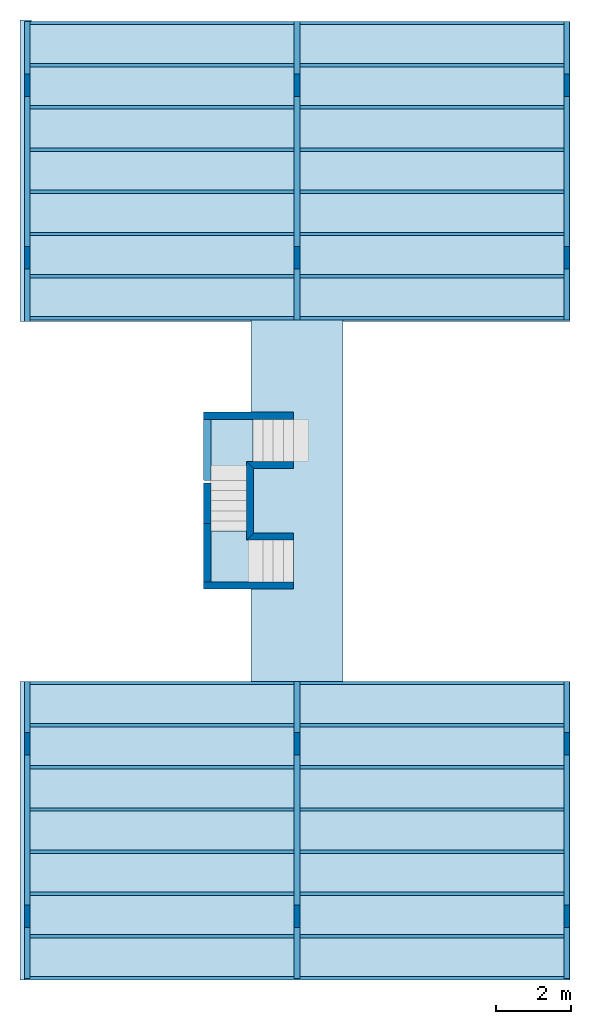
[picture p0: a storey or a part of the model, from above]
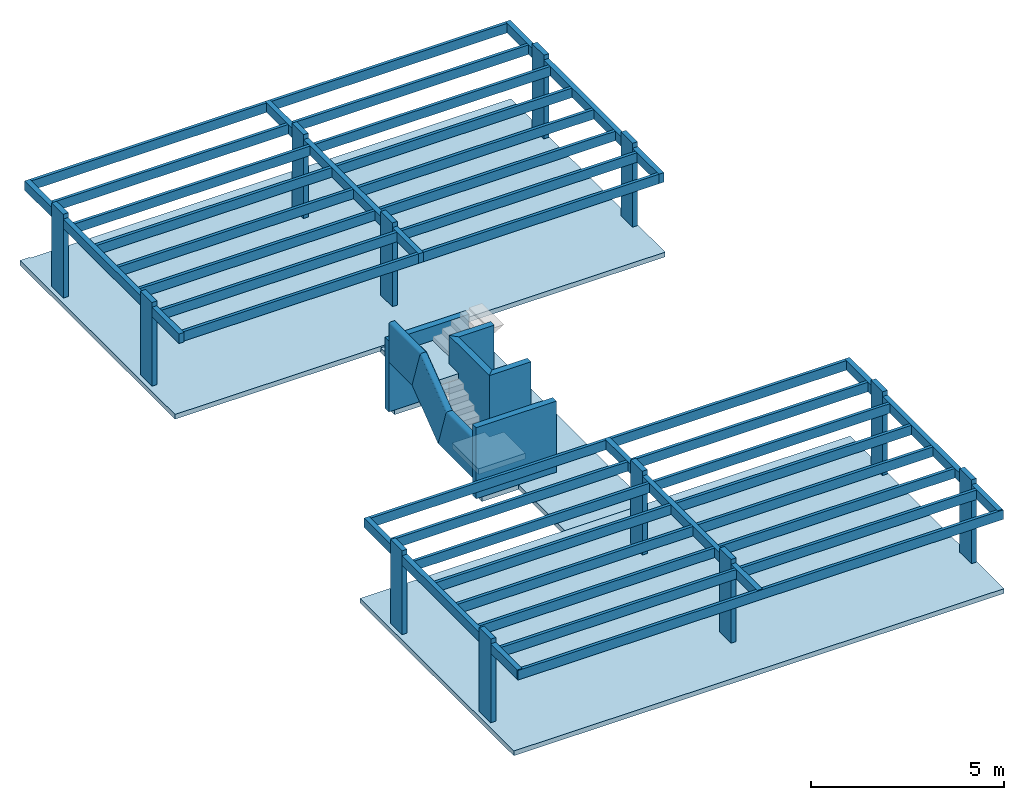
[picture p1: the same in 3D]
Properties of the parts of a building model (IFC4), part 6 of 7

# IfcWall: Concreto Armado Moldado in Loco - Estrutural 50 (48)
Name | In | ID Dinâmico por Classificação | Length (mm) = Comprimento Médio da Parede (mm) = Comprimento da parede no centro (mm) | Elevação à Origem do Projeto (mm) = Elevação ao 1º Nível de Referência (mm) = Elevação ao 2º Nível de Referência (mm) = Elevação ao Nível do Mar (mm) | Volume (Bruto) (m3) | Perímetro na Planta (mm) | Elevação do Topo ao Primeiro Nível de Referência (mm) = Elevação do Topo À Cota Zero (mm) = Elevação do Topo Ao Nível do Mar (mm) = Elevação do Topo Ao Segundo Nível de Referência (mm) | Elevação da Base Ao Primeiro Nível de Referência (mm) = Elevação da Base À Cota Zero (mm) = Elevação da Base Ao Nível do Mar (mm) = Elevação da Base Ao Segundo Nível de Referência (mm) | Comprimento da Linha de Referência (mm) = Comprimento da Face Externa da Parede (Condicional) (mm) = Comprimento da Parede na Face Externa (mm) | Comprimento da Face Interna da Parede (Condicional) (mm) = Comprimento da Parede na Face Interna (mm) | Área da Superfície da Face Interna da Parede (Bruta) (m2) = Área da Superfície da Face Externa da Parede (Bruta) (m2)
APTO4-PAREDE-002 | Primeiro Pavimento | Parede -002 | 470 | 0 | 0.032385 | 1084.34 | 1235 | 100 | 430 | 510 | 0.6477
APTO4-PAREDE-001 | Primeiro Pavimento | Parede -001 | 435 | 0 | 0.0276225 | 970 | 1235 | 100 | 435 | 435 | 0.55245
APTO4-PAREDE-018 | Primeiro Pavimento | Parede -018 | 470 | 0 | 0.032385 | 1084.34 | 1235 | 100 | 430 | 510 | 0.6477
APTO4-PAREDE-016 | Primeiro Pavimento | Parede -016 | 435 | 0 | 0.0276225 | 970 | 1235 | 100 | 435 | 435 | 0.55245
APTO2-PAREDE-016 | Primeiro Pavimento | Parede -016 | 435 | 0 | 0.0276225 | 970 | 1235 | 100 | 435 | 435 | 0.55245
APTO2-PAREDE-018 | Primeiro Pavimento | Parede -018 | 470 | 0 | 0.032385 | 1084.34 | 1235 | 100 | 430 | 510 | 0.6477
APTO2-PAREDE-002 | Primeiro Pavimento | Parede -002 | 470 | 0 | 0.032385 | 1084.34 | 1235 | 100 | 430 | 510 | 0.6477
APTO2-PAREDE-001 | Primeiro Pavimento | Parede -001 | 435 | 0 | 0.0276225 | 970 | 1235 | 100 | 435 | 435 | 0.55245
APTO3-PAREDE-016 | Primeiro Pavimento | Parede -016 | 435 | 0 | 0.0276225 | 970 | 1235 | 100 | 435 | 435 | 0.55245
APTO3-PAREDE-018 | Primeiro Pavimento | Parede -018 | 470 | 0 | 0.032385 | 1084.34 | 1235 | 100 | 430 | 510 | 0.6477
APTO3-PAREDE-002 | Primeiro Pavimento | Parede -002 | 470 | 0 | 0.032385 | 1084.34 | 1235 | 100 | 430 | 510 | 0.6477
APTO3-PAREDE-001 | Primeiro Pavimento | Parede -001 | 435 | 0 | 0.0276225 | 970 | 1235 | 100 | 435 | 435 | 0.55245
APTO1-PAREDE-001 | Primeiro Pavimento | Parede -001 | 435 | 0 | 0.0276225 | 970 | 1235 | 100 | 435 | 435 | 0.55245
APTO1-PAREDE-002 | Primeiro Pavimento | Parede -002 | 470 | 0 | 0.032385 | 1084.34 | 1235 | 100 | 430 | 510 | 0.6477
APTO1-PAREDE-018 | Primeiro Pavimento | Parede -018 | 470 | 0 | 0.032385 | 1084.34 | 1235 | 100 | 430 | 510 | 0.6477
APTO1-PAREDE-016 | Primeiro Pavimento | Parede -016 | 435 | 0 | 0.0276225 | 970 | 1235 | 100 | 435 | 435 | 0.55245
APTO5-PAREDE-016 | Segundo Pavimento | Parede -016 | 435 | 2650 | 0.0276225 | 970 | 3885 | 2750 | 435 | 435 | 0.55245
APTO5-PAREDE-018 | Segundo Pavimento | Parede -018 | 470 | 2650 | 0.032385 | 1084.34 | 3885 | 2750 | 430 | 510 | 0.6477
APTO5-PAREDE-002 | Segundo Pavimento | Parede -002 | 470 | 2650 | 0.032385 | 1084.34 | 3885 | 2750 | 430 | 510 | 0.6477
APTO5-PAREDE-001 | Segundo Pavimento | Parede -001 | 435 | 2650 | 0.0276225 | 970 | 3885 | 2750 | 435 | 435 | 0.55245
APTO6-PAREDE-016 | Segundo Pavimento | Parede -016 | 435 | 2650 | 0.0276225 | 970 | 3885 | 2750 | 435 | 435 | 0.55245
APTO6-PAREDE-018 | Segundo Pavimento | Parede -018 | 470 | 2650 | 0.032385 | 1084.34 | 3885 | 2750 | 430 | 510 | 0.6477
APTO6-PAREDE-002 | Segundo Pavimento | Parede -002 | 470 | 2650 | 0.032385 | 1084.34 | 3885 | 2750 | 430 | 510 | 0.6477
APTO6-PAREDE-001 | Segundo Pavimento | Parede -001 | 435 | 2650 | 0.0276225 | 970 | 3885 | 2750 | 435 | 435 | 0.55245
APTO7-PAREDE-016 | Segundo Pavimento | Parede -016 | 435 | 2650 | 0.0276225 | 970 | 3885 | 2750 | 435 | 435 | 0.55245
APTO7-PAREDE-018 | Segundo Pavimento | Parede -018 | 470 | 2650 | 0.032385 | 1084.34 | 3885 | 2750 | 430 | 510 | 0.6477
APTO7-PAREDE-002 | Segundo Pavimento | Parede -002 | 470 | 2650 | 0.032385 | 1084.34 | 3885 | 2750 | 430 | 510 | 0.6477
APTO7-PAREDE-001 | Segundo Pavimento | Parede -001 | 435 | 2650 | 0.0276225 | 970 | 3885 | 2750 | 435 | 435 | 0.55245
APTO8-PAREDE-016 | Segundo Pavimento | Parede -016 | 435 | 2650 | 0.0276225 | 970 | 3885 | 2750 | 435 | 435 | 0.55245
APTO8-PAREDE-018 | Segundo Pavimento | Parede -018 | 470 | 2650 | 0.032385 | 1084.34 | 3885 | 2750 | 430 | 510 | 0.6477
APTO8-PAREDE-002 | Segundo Pavimento | Parede -002 | 470 | 2650 | 0.032385 | 1084.34 | 3885 | 2750 | 430 | 510 | 0.6477
APTO8-PAREDE-001 | Segundo Pavimento | Parede -001 | 435 | 2650 | 0.0276225 | 970 | 3885 | 2750 | 435 | 435 | 0.55245
APTO9-PAREDE-016 | Terceiro Pavimento | Parede -016 | 435 | 5300 | 0.0276225 | 970 | 6535 | 5400 | 435 | 435 | 0.55245
APTO9-PAREDE-018 | Terceiro Pavimento | Parede -018 | 470 | 5300 | 0.032385 | 1084.34 | 6535 | 5400 | 430 | 510 | 0.6477
APTO9-PAREDE-002 | Terceiro Pavimento | Parede -002 | 470 | 5300 | 0.032385 | 1084.34 | 6535 | 5400 | 430 | 510 | 0.6477
APTO9-PAREDE-001 | Terceiro Pavimento | Parede -001 | 435 | 5300 | 0.0276225 | 970 | 6535 | 5400 | 435 | 435 | 0.55245
APTO10-PAREDE-016 | Terceiro Pavimento | Parede -016 | 435 | 5300 | 0.0276225 | 970 | 6535 | 5400 | 435 | 435 | 0.55245
APTO10-PAREDE-018 | Terceiro Pavimento | Parede -018 | 470 | 5300 | 0.032385 | 1084.34 | 6535 | 5400 | 430 | 510 | 0.6477
APTO10-PAREDE-002 | Terceiro Pavimento | Parede -002 | 470 | 5300 | 0.032385 | 1084.34 | 6535 | 5400 | 430 | 510 | 0.6477
APTO10-PAREDE-001 | Terceiro Pavimento | Parede -001 | 435 | 5300 | 0.0276225 | 970 | 6535 | 5400 | 435 | 435 | 0.55245
APTO11-PAREDE-016 | Terceiro Pavimento | Parede -016 | 435 | 5300 | 0.0276225 | 970 | 6535 | 5400 | 435 | 435 | 0.55245
APTO11-PAREDE-018 | Terceiro Pavimento | Parede -018 | 470 | 5300 | 0.032385 | 1084.34 | 6535 | 5400 | 430 | 510 | 0.6477
APTO11-PAREDE-002 | Terceiro Pavimento | Parede -002 | 470 | 5300 | 0.032385 | 1084.34 | 6535 | 5400 | 430 | 510 | 0.6477
APTO11-PAREDE-001 | Terceiro Pavimento | Parede -001 | 435 | 5300 | 0.0276225 | 970 | 6535 | 5400 | 435 | 435 | 0.55245
APTO12-PAREDE-016 | Terceiro Pavimento | Parede -016 | 435 | 5300 | 0.0276225 | 970 | 6535 | 5400 | 435 | 435 | 0.55245
APTO12-PAREDE-018 | Terceiro Pavimento | Parede -018 | 470 | 5300 | 0.032385 | 1084.34 | 6535 | 5400 | 430 | 510 | 0.6477
APTO12-PAREDE-002 | Terceiro Pavimento | Parede -002 | 470 | 5300 | 0.032385 | 1084.34 | 6535 | 5400 | 430 | 510 | 0.6477
APTO12-PAREDE-001 | Terceiro Pavimento | Parede -001 | 435 | 5300 | 0.0276225 | 970 | 6535 | 5400 | 435 | 435 | 0.55245

# IfcWall: Concreto Armado Moldado in Loco - Estrutural 80 (24)
Classification: Parede (Classificação ARCHICAD); 3E 14 02 00 Parede (NBR 15965-5 3E); Material: Concreto Armado Moldado in Loco - Estrutural 80 mm
Pset_WallCommon - AcousticRating: 0,00; IsExternal: yes; Status: EXISTING
CLASSIFICAÇÕES GERAIS - Transmissão Sonora: 0
SUPERFÍCIES (Mapas) - Superfície da Face (Geral): Concreto - 03
Component Properties - Concreto Armado Moldado in Loco - Estrutural, Tipo de Componente: Nenhum
Qto_WallBaseQuantities - Height: 1685 mm; Width: 80 mm; Concreto Armado Moldado in Loco - Estrutural, Width: 80 mm
ArchiCADQuantities - Altura: 1765 mm; Largura: 80 mm; Elevação ao Piso: -450 mm; Afastamento da Origem: -450 mm; Afastamento do Topo: 0 mm; Espessura: 80 mm; Espessura da Camada de Isolamento: 0 mm; Elevação do Topo Ao Piso de Origem: 1235 mm; Elevação da Base Ao Piso de Origem: -450 mm; Número de Portas: 0; Número de Furos (Número de Aberturas Vazias): 0; Número de Janelas: 0; Número de Pilares: 0; Volume dos Pilares: 0 m3; Altura Máxima da Camada da Parede na Face Interna: 0 mm; Altura Mínima da Camada da Parede na Face Interna: 0 mm; Altura máxima da parede: 1685 mm; Altura mínima da parede: 0 mm; Altura Máxima da Camada da Parede na Face Externa: 0 mm; Altura Mínima da Camada da Parede na Face Externa: 0 mm; Espessura da Camada de Ar: 0 mm; Área das Portas: 0 m2; Soma das Larguras das Portas: 0 mm; Espessura do Componente na Face Interna da Parede: 0 mm; Espessura do Componentena na Face Externa da Parede: 0 mm; Área das Janelas: 0 m2; Soma das Larguras das Janelas: 0 mm; Área Analítica da Superfície das Aberturas da Face Interna: 0 m2; Área Analítica da Superfície das Aberturas da Face Externa: 0 m2; Volume Analítico das Aberturas: 0 m3; Espessura da Parede na Terminação: 80 mm; Área de Superfície do Vão na Parede: 0 m2
ALVENARIAS (Expressão) - Espessura da Argamassa: 10 mm
Component Quantities - Concreto Armado Moldado in Loco - Estrutural, Espessura do Componente: 80 mm; Concreto Armado Moldado in Loco - Estrutural, Altura do Componente Retangular: 1765 mm; Concreto Armado Moldado in Loco - Estrutural, Largura do Componente Retangular: 80 mm; Concreto Armado Moldado in Loco - Estrutural, Área de Seção Transversal do Componente: 0.1412 m2
Name | In | ID Dinâmico por Classificação | Concreto Armado Moldado in Loco - Estrutural, Carbono Incorporado | Concreto Armado Moldado in Loco - Estrutural, Energia Incorporada (MJ) | Length (mm) = Comprimento Médio da Parede (mm) = Comprimento da parede no centro (mm) | GrossFootprintArea (m2) = NetFootprintArea (m2) = Área (m2) = Área da Superfície do Topo (Líquida) (m2) | GrossSideArea (m2) = NetSideArea (m2) = Área da Superfície (m2) = Área da Superfície da Base (Líquida) (m2) = Área da Superfície da Face Interna da Parede (Líquida) (m2) = Área da Superfície da Face Externa da Parede (Líquida) (m2) = Área da Superfície da Face Interna da Parede (Condicional) (m2) = Área da Superfície da Face Externa da Parede (Condicional) (m2) = Concreto Armado Moldado in Loco - Estrutural, Área de Componente Projetada (Líquida) (m2) = Concreto Armado Moldado in Loco - Estrutural, Área de Componente Projetada (Bruta) (m2) = Concreto Armado Moldado in Loco - Estrutural, Área de Componente Projetada (Condicional) (m2) | GrossVolume (m3) = NetVolume (m3) = Volume (Líquido) (m3) = Volume (Condicional) (m3) = Concreto Armado Moldado in Loco - Estrutural, Volume Componente (Líquido) (m3) = Concreto Armado Moldado in Loco - Estrutural, Volume do componente (Bruto) (m3) = Concreto Armado Moldado in Loco - Estrutural, Volume Componente (Condicional) (m3) | Elevação à Origem do Projeto (mm) = Elevação ao 1º Nível de Referência (mm) = Elevação ao 2º Nível de Referência (mm) = Elevação ao Nível do Mar (mm) = Elevação da Base Ao Primeiro Nível de Referência (mm) = Elevação da Base À Cota Zero (mm) = Elevação da Base Ao Nível do Mar (mm) = Elevação da Base Ao Segundo Nível de Referência (mm) | Comprimento 3D (mm) = Comprimento da Linha de Referência (mm) = Comprimento da Face Externa da Parede (Condicional) (mm) = Comprimento da Parede na Face Externa (mm) | Volume (Bruto) (m3) | Perímetro na Planta (mm) | Elevação do Topo ao Primeiro Nível de Referência (mm) = Elevação do Topo À Cota Zero (mm) = Elevação do Topo Ao Nível do Mar (mm) = Elevação do Topo Ao Segundo Nível de Referência (mm) | Área da Superfície da Borda (Líquida) (m2) = Área da Superfície da Face (Geral) (m2) | Comprimento da Face Interna da Parede (Condicional) (mm) = Comprimento da Parede na Face Interna (mm) | Área da Superfície da Face Interna da Parede (Bruta) (m2) = Área da Superfície da Face Externa da Parede (Bruta) (m2) | Concreto Armado Moldado in Loco - Estrutural, Massa (kg)
APTO4-PAREDE-015 | Primeiro Pavimento | Parede -015 | 514.045 (kgCO₂) | 4949.28 | 6955 | 0.5584 | 11.0633 | 0.885064 | -450 | 6980 | 0.985576 | 14084.3 | 1235 | 0.6852 | 6930 | 12.3197 | 2124.15
APTO4-PAREDE-017 | Primeiro Pavimento | Parede -017 | 412.414 (kgCO₂) | 3970.77 | 5575 | 0.448 | 8.876 | 0.71008 | -450 | 5600 | 0.79072 | 11324.3 | 1235 | 0.5748 | 5550 | 9.884 | 1704.19
APTO2-PAREDE-017 | Primeiro Pavimento | Parede -017 | 412.414 (kgCO₂) | 3970.77 | 5575 | 0.448 | 8.876 | 0.71008 | -450 | 5600 | 0.79072 | 11324.3 | 1235 | 0.5748 | 5550 | 9.884 | 1704.19
APTO2-PAREDE-015 | Primeiro Pavimento | Parede -015 | 514.045 (kgCO₂) | 4949.28 | 6955 | 0.5584 | 11.0633 | 0.885064 | -450 | 6980 | 0.985576 | 14084.3 | 1235 | 0.6852 | 6930 | 12.3197 | 2124.15
APTO3-PAREDE-017 | Primeiro Pavimento | Parede -017 | 412.414 (kgCO₂) | 3970.77 | 5575 | 0.448 | 8.876 | 0.71008 | -450 | 5600 | 0.79072 | 11324.3 | 1235 | 0.5748 | 5550 | 9.884 | 1704.19
APTO3-PAREDE-015 | Primeiro Pavimento | Parede -015 | 514.045 (kgCO₂) | 4949.28 | 6955 | 0.5584 | 11.0633 | 0.885064 | -450 | 6980 | 0.985576 | 14084.3 | 1235 | 0.6852 | 6930 | 12.3197 | 2124.15
APTO1-PAREDE-015 | Primeiro Pavimento | Parede -015 | 514.045 (kgCO₂) | 4949.28 | 6955 | 0.5584 | 11.0633 | 0.885064 | -450 | 6980 | 0.985576 | 14084.3 | 1235 | 0.6852 | 6930 | 12.3197 | 2124.15
APTO1-PAREDE-017 | Primeiro Pavimento | Parede -017 | 412.414 (kgCO₂) | 3970.77 | 5575 | 0.448 | 8.876 | 0.71008 | -450 | 5600 | 0.79072 | 11324.3 | 1235 | 0.5748 | 5550 | 9.884 | 1704.19
APTO5-PAREDE-017 | Segundo Pavimento | Parede -017 | 412.414 (kgCO₂) | 3970.77 | 5575 | 0.448 | 8.876 | 0.71008 | 2200 | 5600 | 0.79072 | 11324.3 | 3885 | 0.5748 | 5550 | 9.884 | 1704.19
APTO5-PAREDE-015 | Segundo Pavimento | Parede -015 | 514.045 (kgCO₂) | 4949.28 | 6955 | 0.5584 | 11.0633 | 0.885064 | 2200 | 6980 | 0.985576 | 14084.3 | 3885 | 0.6852 | 6930 | 12.3197 | 2124.15
APTO6-PAREDE-017 | Segundo Pavimento | Parede -017 | 412.414 (kgCO₂) | 3970.77 | 5575 | 0.448 | 8.876 | 0.71008 | 2200 | 5600 | 0.79072 | 11324.3 | 3885 | 0.5748 | 5550 | 9.884 | 1704.19
APTO6-PAREDE-015 | Segundo Pavimento | Parede -015 | 514.045 (kgCO₂) | 4949.28 | 6955 | 0.5584 | 11.0633 | 0.885064 | 2200 | 6980 | 0.985576 | 14084.3 | 3885 | 0.6852 | 6930 | 12.3197 | 2124.15
APTO7-PAREDE-017 | Segundo Pavimento | Parede -017 | 412.414 (kgCO₂) | 3970.77 | 5575 | 0.448 | 8.876 | 0.71008 | 2200 | 5600 | 0.79072 | 11324.3 | 3885 | 0.5748 | 5550 | 9.884 | 1704.19
APTO7-PAREDE-015 | Segundo Pavimento | Parede -015 | 514.045 (kgCO₂) | 4949.28 | 6955 | 0.5584 | 11.0633 | 0.885064 | 2200 | 6980 | 0.985576 | 14084.3 | 3885 | 0.6852 | 6930 | 12.3197 | 2124.15
APTO8-PAREDE-017 | Segundo Pavimento | Parede -017 | 412.414 (kgCO₂) | 3970.77 | 5575 | 0.448 | 8.876 | 0.71008 | 2200 | 5600 | 0.79072 | 11324.3 | 3885 | 0.5748 | 5550 | 9.884 | 1704.19
APTO8-PAREDE-015 | Segundo Pavimento | Parede -015 | 514.045 (kgCO₂) | 4949.28 | 6955 | 0.5584 | 11.0633 | 0.885064 | 2200 | 6980 | 0.985576 | 14084.3 | 3885 | 0.6852 | 6930 | 12.3197 | 2124.15
APTO9-PAREDE-017 | Terceiro Pavimento | Parede -017 | 412.414 (kgCO₂) | 3970.77 | 5575 | 0.448 | 8.876 | 0.71008 | 4850 | 5600 | 0.79072 | 11324.3 | 6535 | 0.5748 | 5550 | 9.884 | 1704.19
APTO9-PAREDE-015 | Terceiro Pavimento | Parede -015 | 514.045 (kgCO₂) | 4949.28 | 6955 | 0.5584 | 11.0633 | 0.885064 | 4850 | 6980 | 0.985576 | 14084.3 | 6535 | 0.6852 | 6930 | 12.3197 | 2124.15
APTO10-PAREDE-017 | Terceiro Pavimento | Parede -017 | 412.414 (kgCO₂) | 3970.77 | 5575 | 0.448 | 8.876 | 0.71008 | 4850 | 5600 | 0.79072 | 11324.3 | 6535 | 0.5748 | 5550 | 9.884 | 1704.19
APTO10-PAREDE-015 | Terceiro Pavimento | Parede -015 | 514.045 (kgCO₂) | 4949.28 | 6955 | 0.5584 | 11.0633 | 0.885064 | 4850 | 6980 | 0.985576 | 14084.3 | 6535 | 0.6852 | 6930 | 12.3197 | 2124.15
APTO11-PAREDE-017 | Terceiro Pavimento | Parede -017 | 412.414 (kgCO₂) | 3970.77 | 5575 | 0.448 | 8.876 | 0.71008 | 4850 | 5600 | 0.79072 | 11324.3 | 6535 | 0.5748 | 5550 | 9.884 | 1704.19
APTO11-PAREDE-015 | Terceiro Pavimento | Parede -015 | 514.045 (kgCO₂) | 4949.28 | 6955 | 0.5584 | 11.0633 | 0.885064 | 4850 | 6980 | 0.985576 | 14084.3 | 6535 | 0.6852 | 6930 | 12.3197 | 2124.15
APTO12-PAREDE-017 | Terceiro Pavimento | Parede -017 | 412.414 (kgCO₂) | 3970.77 | 5575 | 0.448 | 8.876 | 0.71008 | 4850 | 5600 | 0.79072 | 11324.3 | 6535 | 0.5748 | 5550 | 9.884 | 1704.19
APTO12-PAREDE-015 | Terceiro Pavimento | Parede -015 | 514.045 (kgCO₂) | 4949.28 | 6955 | 0.5584 | 11.0633 | 0.885064 | 4850 | 6980 | 0.985576 | 14084.3 | 6535 | 0.6852 | 6930 | 12.3197 | 2124.15

# IfcWall: GENÉRICO - VEDAÇÃO EXTERNA 140 (12)
Classification: Parede (Classificação ARCHICAD); 3E 14 02 00 Parede (NBR 15965-5 3E); Material: GENÉRICO - VEDAÇÃO EXTERNA 140 mm
Pset_WallCommon - AcousticRating: 0,00; IsExternal: yes; Status: EXISTING
CLASSIFICAÇÕES GERAIS - Transmissão Sonora: 0
EXPRESSÕES DE TEXTO (Expressão) - ID Dinâmico por Classificação: Parede -004
SUPERFÍCIES (Mapas) - Superfície da Face (Geral): Pintura - Sienna Areia
Component Properties - GENÉRICO - VEDAÇÃO EXTERNA, Tipo de Componente: Nenhum
Qto_WallBaseQuantities - Length: 1580 mm; Height: 2200 mm; Width: 140 mm; GENÉRICO - VEDAÇÃO EXTERNA, Width: 140 mm
ArchiCADQuantities - Altura: 2200 mm; Largura: 140 mm; Elevação ao Piso: 0 mm; Afastamento da Origem: 0 mm; Afastamento do Topo: -450 mm; Espessura: 140 mm; Espessura da Camada de Isolamento: 0 mm; Perímetro na Planta: 3440 mm; Elevação do Topo Ao Piso de Origem: 2200 mm; Elevação da Base Ao Piso de Origem: 0 mm; Número de Portas: 1; Número de Furos (Número de Aberturas Vazias): 0; Número de Janelas: 0; Número de Pilares: 0; Volume dos Pilares: 0 m3; Altura Máxima da Camada da Parede na Face Interna: 0 mm; Altura Mínima da Camada da Parede na Face Interna: 0 mm; Altura máxima da parede: 2200 mm; Altura Máxima da Camada da Parede na Face Externa: 0 mm; Altura Mínima da Camada da Parede na Face Externa: 0 mm; Espessura da Camada de Ar: 0 mm; Área das Portas: 1.89 m2; Soma das Larguras das Portas: 900 mm; Espessura do Componente na Face Interna da Parede: 0 mm; Espessura do Componentena na Face Externa da Parede: 0 mm; Área das Janelas: 0 m2; Soma das Larguras das Janelas: 0 mm; Área Analítica da Superfície das Aberturas da Face Interna: 1.89 m2; Área Analítica da Superfície das Aberturas da Face Externa: 1.89 m2; Comprimento Médio da Parede: 1580 mm; Volume Analítico das Aberturas: 0.2646 m3; Comprimento da Linha de Referência: 1580 mm; Comprimento da Face Interna da Parede (Condicional): 680 mm; Comprimento da Face Externa da Parede (Condicional): 680 mm; Espessura da Parede na Terminação: 140 mm; Comprimento da parede no centro: 1580 mm; Comprimento da Parede na Face Interna: 1580 mm; Comprimento da Parede na Face Externa: 1580 mm; Área de Superfície do Vão na Parede: 0 m2
ALVENARIAS (Expressão) - Espessura da Argamassa: 10 mm
Component Quantities - GENÉRICO - VEDAÇÃO EXTERNA, Espessura do Componente: 140 mm; GENÉRICO - VEDAÇÃO EXTERNA, Altura do Componente Retangular: 2200 mm; GENÉRICO - VEDAÇÃO EXTERNA, Largura do Componente Retangular: 140 mm; GENÉRICO - VEDAÇÃO EXTERNA, Área de Seção Transversal do Componente: 0.308 m2
Name | In | GENÉRICO - VEDAÇÃO EXTERNA, Carbono Incorporado | GENÉRICO - VEDAÇÃO EXTERNA, Energia Incorporada (MJ) | GrossFootprintArea (m2) = NetFootprintArea (m2) = Área (m2) = Área da Superfície do Topo (Líquida) (m2) | GrossSideArea (m2) = Área da Superfície da Face Interna da Parede (Condicional) (m2) = Área da Superfície da Face Externa da Parede (Condicional) (m2) = GENÉRICO - VEDAÇÃO EXTERNA, Área de Componente Projetada (Bruta) (m2) = GENÉRICO - VEDAÇÃO EXTERNA, Área de Componente Projetada (Condicional) (m2) | NetSideArea (m2) = Área da Superfície (m2) = Área da Superfície da Base (Líquida) (m2) = Área da Superfície da Face Interna da Parede (Líquida) (m2) = Área da Superfície da Face Externa da Parede (Líquida) (m2) = GENÉRICO - VEDAÇÃO EXTERNA, Área de Componente Projetada (Líquida) (m2) | GrossVolume (m3) = Volume (Condicional) (m3) = GENÉRICO - VEDAÇÃO EXTERNA, Volume do componente (Bruto) (m3) = GENÉRICO - VEDAÇÃO EXTERNA, Volume Componente (Condicional) (m3) | NetVolume (m3) = Volume (Líquido) (m3) = GENÉRICO - VEDAÇÃO EXTERNA, Volume Componente (Líquido) (m3) | Elevação à Origem do Projeto (mm) = Elevação ao 1º Nível de Referência (mm) = Elevação ao 2º Nível de Referência (mm) = Elevação ao Nível do Mar (mm) = Elevação da Base Ao Primeiro Nível de Referência (mm) = Elevação da Base À Cota Zero (mm) = Elevação da Base Ao Nível do Mar (mm) = Elevação da Base Ao Segundo Nível de Referência (mm) | Comprimento 3D (mm) | Volume (Bruto) (m3) | Elevação do Topo ao Primeiro Nível de Referência (mm) = Elevação do Topo À Cota Zero (mm) = Elevação do Topo Ao Nível do Mar (mm) = Elevação do Topo Ao Segundo Nível de Referência (mm) | Área da Superfície da Borda (Líquida) (m2) = Área da Superfície da Face (Geral) (m2) | Altura mínima da parede (mm) | Área da Superfície da Face Interna da Parede (Bruta) (m2) = Área da Superfície da Face Externa da Parede (Bruta) (m2) | GENÉRICO - VEDAÇÃO EXTERNA, Massa (kg)
APTO4-PAREDE-004 | Primeiro Pavimento | 76.737 (kgCO₂) | 959.213 | 0.0952 | 3.476 | 1.586 | 0.48664 | 0.22204 | 0 | 1580 | 0.48664 | 2200 | 0.9324 | 2200 | 3.476 | 213.158
APTO2-PAREDE-004 | Primeiro Pavimento | 76.737 (kgCO₂) | 959.213 | 0.0952 | 3.476 | 1.586 | 0.48664 | 0.22204 | 0 | 1580 | 0.48664 | 2200 | 0.9324 | 2200 | 3.476 | 213.158
APTO3-PAREDE-004 | Primeiro Pavimento | 56.5125 (kgCO₂) | 706.406 | 0.0686 | 3.058 | 1.168 | 0.42812 | 0.16352 | 0 | 1390 | 0.51744 | 2200 | 0.5712 | 2100 | 3.696 | 156.979
APTO1-PAREDE-004 | Primeiro Pavimento | 56.5125 (kgCO₂) | 706.406 | 0.0686 | 3.058 | 1.168 | 0.42812 | 0.16352 | 0 | 1390 | 0.51744 | 2200 | 0.5712 | 2100 | 3.696 | 156.979
APTO5-PAREDE-004 | Segundo Pavimento | 56.5125 (kgCO₂) | 706.406 | 0.0686 | 3.058 | 1.168 | 0.42812 | 0.16352 | 2650 | 1390 | 0.51744 | 4850 | 0.5712 | 2100 | 3.696 | 156.979
APTO6-PAREDE-004 | Segundo Pavimento | 76.737 (kgCO₂) | 959.213 | 0.0952 | 3.476 | 1.586 | 0.48664 | 0.22204 | 2650 | 1580 | 0.48664 | 4850 | 0.9324 | 2200 | 3.476 | 213.158
APTO7-PAREDE-004 | Segundo Pavimento | 56.5125 (kgCO₂) | 706.406 | 0.0686 | 3.058 | 1.168 | 0.42812 | 0.16352 | 2650 | 1390 | 0.51744 | 4850 | 0.5712 | 2100 | 3.696 | 156.979
APTO8-PAREDE-004 | Segundo Pavimento | 76.737 (kgCO₂) | 959.213 | 0.0952 | 3.476 | 1.586 | 0.48664 | 0.22204 | 2650 | 1580 | 0.48664 | 4850 | 0.9324 | 2200 | 3.476 | 213.158
APTO9-PAREDE-004 | Terceiro Pavimento | 56.5125 (kgCO₂) | 706.406 | 0.0686 | 3.058 | 1.168 | 0.42812 | 0.16352 | 5300 | 1390 | 0.51744 | 7500 | 0.5712 | 2100 | 3.696 | 156.979
APTO10-PAREDE-004 | Terceiro Pavimento | 76.737 (kgCO₂) | 959.213 | 0.0952 | 3.476 | 1.586 | 0.48664 | 0.22204 | 5300 | 1580 | 0.48664 | 7500 | 0.9324 | 2200 | 3.476 | 213.158
APTO11-PAREDE-004 | Terceiro Pavimento | 56.5125 (kgCO₂) | 706.406 | 0.0686 | 3.058 | 1.168 | 0.42812 | 0.16352 | 5300 | 1390 | 0.51744 | 7500 | 0.5712 | 2100 | 3.696 | 156.979
APTO12-PAREDE-004 | Terceiro Pavimento | 76.737 (kgCO₂) | 959.213 | 0.0952 | 3.476 | 1.586 | 0.48664 | 0.22204 | 5300 | 1580 | 0.48664 | 7500 | 0.9324 | 2200 | 3.476 | 213.158

# IfcWall: GENÉRICO - VEDAÇÃO EXTERNA 190 (26)
Classification: Parede (Classificação ARCHICAD); 3E 14 02 00 Parede (NBR 15965-5 3E); Material: GENÉRICO - VEDAÇÃO EXTERNA 190 mm
Pset_WallCommon - AcousticRating: 0,00; Status: EXISTING
CLASSIFICAÇÕES GERAIS - Transmissão Sonora: 0
SUPERFÍCIES (Mapas) - Superfície da Face (Geral): Pintura - Sienna Areia
Component Properties - GENÉRICO - VEDAÇÃO EXTERNA, Tipo de Componente: Nenhum
Qto_WallBaseQuantities - Width: 190 mm; GENÉRICO - VEDAÇÃO EXTERNA, Width: 190 mm
ArchiCADQuantities - Largura: 190 mm; Espessura: 190 mm; Espessura da Camada de Isolamento: 0 mm; Número de Portas: 0; Número de Furos (Número de Aberturas Vazias): 0; Número de Janelas: 0; Volume dos Pilares: 0 m3; Altura Máxima da Camada da Parede na Face Interna: 0 mm; Altura Mínima da Camada da Parede na Face Interna: 0 mm; Altura Máxima da Camada da Parede na Face Externa: 0 mm; Altura Mínima da Camada da Parede na Face Externa: 0 mm; Espessura da Camada de Ar: 0 mm; Área das Portas: 0 m2; Soma das Larguras das Portas: 0 mm; Espessura do Componente na Face Interna da Parede: 0 mm; Espessura do Componentena na Face Externa da Parede: 0 mm; Área das Janelas: 0 m2; Soma das Larguras das Janelas: 0 mm; Espessura da Parede na Terminação: 190 mm; Área de Superfície do Vão na Parede: 0 m2
ALVENARIAS (Expressão) - Espessura da Argamassa: 10 mm
Component Quantities - GENÉRICO - VEDAÇÃO EXTERNA, Espessura do Componente: 190 mm; GENÉRICO - VEDAÇÃO EXTERNA, Largura do Componente Retangular: 190 mm
Name | In | IsExternal | ID Dinâmico por Classificação | GENÉRICO - VEDAÇÃO EXTERNA, Carbono Incorporado | GENÉRICO - VEDAÇÃO EXTERNA, Energia Incorporada (MJ) | Length (mm) = Comprimento Médio da Parede (mm) = Comprimento da Linha de Referência (mm) = Comprimento da Face Interna da Parede (Condicional) (mm) = Comprimento da Face Externa da Parede (Condicional) (mm) = Comprimento da parede no centro (mm) = Comprimento da Parede na Face Interna (mm) = Comprimento da Parede na Face Externa (mm) | Height (mm) = Altura máxima da parede (mm) | GrossFootprintArea (m2) = NetFootprintArea (m2) = Área (m2) = Área da Superfície do Topo (Líquida) (m2) | GrossSideArea (m2) = NetSideArea (m2) | GrossVolume (m3) = NetVolume (m3) = Volume (Líquido) (m3) = Volume (Condicional) (m3) = GENÉRICO - VEDAÇÃO EXTERNA, Volume Componente (Líquido) (m3) = GENÉRICO - VEDAÇÃO EXTERNA, Volume do componente (Bruto) (m3) = GENÉRICO - VEDAÇÃO EXTERNA, Volume Componente (Condicional) (m3) | Altura (mm) = GENÉRICO - VEDAÇÃO EXTERNA, Altura do Componente Retangular (mm) | Elevação à Origem do Projeto (mm) = Elevação ao 1º Nível de Referência (mm) = Elevação ao 2º Nível de Referência (mm) = Elevação ao Nível do Mar (mm) = Elevação da Base Ao Primeiro Nível de Referência (mm) = Elevação da Base À Cota Zero (mm) = Elevação da Base Ao Nível do Mar (mm) = Elevação da Base Ao Segundo Nível de Referência (mm) | Elevação ao Piso (mm) = Afastamento da Origem (mm) = Elevação da Base Ao Piso de Origem (mm) | Afastamento do Topo (mm) | Área da Superfície (m2) = Área da Superfície da Base (Líquida) (m2) = Área da Superfície da Face Externa da Parede (Líquida) (m2) = Área da Superfície da Face Externa da Parede (Condicional) (m2) | Comprimento 3D (mm) | Volume (Bruto) (m3) | Perímetro na Planta (mm) | Elevação do Topo ao Primeiro Nível de Referência (mm) = Elevação do Topo À Cota Zero (mm) = Elevação do Topo Ao Nível do Mar (mm) = Elevação do Topo Ao Segundo Nível de Referência (mm) | Elevação do Topo Ao Piso de Origem (mm) | Área da Superfície da Borda (Líquida) (m2) = Área da Superfície da Face (Geral) (m2) | Número de Pilares | Altura mínima da parede (mm) | Área Analítica da Superfície das Aberturas da Face Interna (m2) | Área Analítica da Superfície das Aberturas da Face Externa (m2) | Área da Superfície da Face Interna da Parede (Líquida) (m2) = Área da Superfície da Face Interna da Parede (Condicional) (m2) | Volume Analítico das Aberturas (m3) | Área da Superfície da Face Interna da Parede (Bruta) (m2) = Área da Superfície da Face Externa da Parede (Bruta) (m2) | GENÉRICO - VEDAÇÃO EXTERNA, Massa (kg) | GENÉRICO - VEDAÇÃO EXTERNA, Área de Componente Projetada (Líquida) (m2) = GENÉRICO - VEDAÇÃO EXTERNA, Área de Componente Projetada (Bruta) (m2) = GENÉRICO - VEDAÇÃO EXTERNA, Área de Componente Projetada (Condicional) (m2) | GENÉRICO - VEDAÇÃO EXTERNA, Área de Seção Transversal do Componente (m2)
PAREDE-039 | Pavimento Terreo | yes | Parede -039 | 354.586 (kgCO₂) | 4432.32 | 2400 | 2250 | 0.456 | 5.4 | 1.026 | 2250 | -2700 | -50 | -450 | 5.4 | 2400 | 1.026 | 5180 | -450 | 2200 | 1.767 | 0 | 2250 | 0 | 0 | 5.4 | 0 | 5.4 | 984.96 | 5.4 | 0.4275
PAREDE-038 | Pavimento Terreo | yes | Parede -038 | 354.586 (kgCO₂) | 4432.32 | 2400 | 2250 | 0.456 | 5.4 | 1.026 | 2250 | -2700 | -50 | -450 | 5.4 | 2400 | 1.026 | 5180 | -450 | 2200 | 1.767 | 0 | 2250 | 0 | 0 | 5.4 | 0 | 5.4 | 984.96 | 5.4 | 0.4275
APTO4-PAREDE-013 | Primeiro Pavimento | yes | Parede -013 | 1051.33 (kgCO₂) | 13141.6 | 8000 | 2500 | 1.34 | 19.892 | 3.04204 | 2650 | 0 | 0 | 0 | 19.784 | 8000 | 4.028 | 16380 | 2500 | 2500 | 2.2615 | 2 | 0 | 0 | 0 | 20 | 0 | 21.2 | 2920.36 | 20 | 0.5035
CIRC1-PAREDE-021 | Primeiro Pavimento | yes | Parede -021 | 370.345 (kgCO₂) | 4629.31 | 2400 | 2350 | 0.456 | 5.64 | 1.0716 | 2350 | -150 | -150 | -450 | 5.64 | 2400 | 1.0716 | 5180 | 2200 | 2200 | 1.805 | 0 | 2350 | 0 | 0 | 5.64 | 0 | 5.64 | 1028.74 | 5.64 | 0.4465
CIRC1-PAREDE-020 | Primeiro Pavimento | yes | Parede -020 | 370.345 (kgCO₂) | 4629.31 | 2400 | 2350 | 0.456 | 5.64 | 1.0716 | 2350 | -150 | -150 | -450 | 5.64 | 2400 | 1.0716 | 5180 | 2200 | 2200 | 1.805 | 0 | 2350 | 0 | 0 | 5.64 | 0 | 5.64 | 1028.74 | 5.64 | 0.4465
APTO2-PAREDE-013 | Primeiro Pavimento | yes | Parede -013 | 1051.33 (kgCO₂) | 13141.6 | 8000 | 2500 | 1.34 | 19.892 | 3.04204 | 2650 | 0 | 0 | 0 | 19.784 | 8000 | 4.028 | 16380 | 2500 | 2500 | 2.2615 | 2 | 0 | 0 | -3.55271e-15 | 20 | 0 | 21.2 | 2920.36 | 20 | 0.5035
APTO3-PAREDE-013 | Primeiro Pavimento | yes | Parede -013 | 1051.33 (kgCO₂) | 13141.6 | 8000 | 2500 | 1.34 | 19.892 | 3.04204 | 2650 | 0 | 0 | 0 | 19.784 | 8000 | 4.028 | 16380 | 2500 | 2500 | 2.2615 | 2 | 0 | 0 | 0 | 20 | 0 | 21.2 | 2920.36 | 20 | 0.5035
APTO1-PAREDE-013 | Primeiro Pavimento | yes | Parede -013 | 1051.33 (kgCO₂) | 13141.6 | 8000 | 2500 | 1.34 | 19.892 | 3.04204 | 2650 | 0 | 0 | 0 | 19.784 | 8000 | 4.028 | 16380 | 2500 | 2500 | 2.2615 | 2 | 0 | 0 | 0 | 20 | 0 | 21.2 | 2920.36 | 20 | 0.5035
CIRC1-PAREDE-029 | Primeiro Pavimento | no | Parede -029 | 1023.39 (kgCO₂) | 12792.3 | 7825 | 2500 | 1.30675 | 19.3735 | 2.96119 | 2500 | 0 | 0 | -150 | 19.3735 | 7825 | 3.7754 | 16030 | 2500 | 2500 | 2.01255 | 2 | 0 | 0 | 0 | 19.3735 | -4.44089e-16 | 19.8705 | 2842.74 | 19.3735 | 0.475
CIRC1-PAREDE-026 | Primeiro Pavimento | no | Parede -026 | 1020.4 (kgCO₂) | 12755 | 7825 | 2470 | 1.30675 | 19.1577 | 2.95256 | 2470 | 0 | 0 | -180 | 19.1577 | 7825 | 3.73079 | 16030 | 2470 | 2470 | 2.01255 | 2 | 0 | 0 | 0 | 19.1577 | -4.44089e-16 | 19.6358 | 2834.45 | 19.1576 | 0.4693
CIRC2-PAREDE-020 | Segundo Pavimento | yes | Parede -020 | 370.345 (kgCO₂) | 4629.31 | 2400 | 2350 | 0.456 | 5.64 | 1.0716 | 2350 | 2500 | -150 | -450 | 5.64 | 2400 | 1.0716 | 5180 | 4850 | 2200 | 1.805 | 0 | 2350 | 0 | 0 | 5.64 | 0 | 5.64 | 1028.74 | 5.64 | 0.4465
CIRC2-PAREDE-026 | Segundo Pavimento | no | Parede -026 | 1020.4 (kgCO₂) | 12755 | 7825 | 2470 | 1.30675 | 19.1577 | 2.95256 | 2470 | 2650 | 0 | -180 | 19.1577 | 7825 | 3.73079 | 16030 | 5120 | 2470 | 2.01255 | 2 | 0 | -3.55271e-15 | 0 | 19.1577 | 0 | 19.6358 | 2834.45 | 19.1576 | 0.4693
CIRC2-PAREDE-029 | Segundo Pavimento | no | Parede -029 | 1116.62 (kgCO₂) | 13957.8 | 7825 | 2500 | 1.30675 | 19.3735 | 3.23096 | 2500 | 2650 | 0 | -150 | 19.3735 | 7825 | 3.7754 | 16030 | 5150 | 2500 | 2.9118 | 2 | 0 | 0 | 0 | 19.3735 | 8.88178e-16 | 19.8705 | 3101.73 | 19.3735 | 0.475
CIRC2-PAREDE-021 | Segundo Pavimento | yes | Parede -021 | 370.345 (kgCO₂) | 4629.31 | 2400 | 2350 | 0.456 | 5.64 | 1.0716 | 2350 | 2500 | -150 | -450 | 5.64 | 2400 | 1.0716 | 5180 | 4850 | 2200 | 1.805 | 0 | 2350 | 0 | 0 | 5.64 | 0 | 5.64 | 1028.74 | 5.64 | 0.4465
APTO5-PAREDE-013 | Segundo Pavimento | yes | Parede -013 | 1051.33 (kgCO₂) | 13141.6 | 8000 | 2500 | 1.34 | 19.892 | 3.04204 | 2650 | 2650 | 0 | 0 | 19.784 | 8000 | 4.028 | 16380 | 5150 | 2500 | 2.2615 | 2 | 0 | 0 | 0 | 20 | 0 | 21.2 | 2920.36 | 20 | 0.5035
APTO6-PAREDE-013 | Segundo Pavimento | yes | Parede -013 | 1051.33 (kgCO₂) | 13141.6 | 8000 | 2500 | 1.34 | 19.892 | 3.04204 | 2650 | 2650 | 0 | 0 | 19.784 | 8000 | 4.028 | 16380 | 5150 | 2500 | 2.2615 | 2 | 0 | 0 | -7.10543e-15 | 20 | -2.22045e-15 | 21.2 | 2920.36 | 20 | 0.5035
APTO7-PAREDE-013 | Segundo Pavimento | yes | Parede -013 | 1051.33 (kgCO₂) | 13141.6 | 8000 | 2500 | 1.34 | 19.892 | 3.04204 | 2650 | 2650 | 0 | 0 | 19.784 | 8000 | 4.028 | 16380 | 5150 | 2500 | 2.2615 | 2 | 0 | 0 | 0 | 20 | 0 | 21.2 | 2920.36 | 20 | 0.5035
APTO8-PAREDE-013 | Segundo Pavimento | yes | Parede -013 | 1051.33 (kgCO₂) | 13141.6 | 8000 | 2500 | 1.34 | 19.892 | 3.04204 | 2650 | 2650 | 0 | 0 | 19.784 | 8000 | 4.028 | 16380 | 5150 | 2500 | 2.2615 | 2 | 0 | 0 | 0 | 20 | 0 | 21.2 | 2920.36 | 20 | 0.5035
CIRC3-PAREDE-026 | Terceiro Pavimento | no | Parede -026 | 1020.4 (kgCO₂) | 12755 | 7825 | 2470 | 1.30675 | 19.1577 | 2.95256 | 2470 | 5300 | 0 | -180 | 19.1577 | 7825 | 3.73079 | 16030 | 7770 | 2470 | 2.01255 | 2 | 0 | 0 | 0 | 19.1577 | 0 | 19.6358 | 2834.45 | 19.1576 | 0.4693
CIRC3-PAREDE-030 | Terceiro Pavimento | yes | Parede -030 | 370.345 (kgCO₂) | 4629.31 | 2400 | 2350 | 0.456 | 5.64 | 1.0716 | 2350 | 5150 | -150 | -450 | 5.64 | 2400 | 1.0716 | 5180 | 7500 | 2200 | 1.805 | 0 | 2350 | 0 | 0 | 5.64 | 0 | 5.64 | 1028.74 | 5.64 | 0.4465
CIRC3-PAREDE-029 | Terceiro Pavimento | no | Parede -029 | 1116.62 (kgCO₂) | 13957.8 | 7825 | 2500 | 1.30675 | 19.3735 | 3.23096 | 2500 | 5300 | 0 | -150 | 19.3735 | 7825 | 3.7754 | 16030 | 7800 | 2500 | 2.9118 | 2 | 0 | 0 | 0 | 19.3735 | 0 | 19.8705 | 3101.73 | 19.3735 | 0.475
APTO9-PAREDE-013 | Terceiro Pavimento | yes | Parede -013 | 1051.67 (kgCO₂) | 13145.9 | 8000 | 2650 | 1.34 | 19.8973 | 3.04304 | 2650 | 5300 | 0 | 0 | 19.7893 | 8000 | 4.028 | 16380 | 7950 | 2650 | 2.29665 | 2 | 0 | 0 | 0 | 20.0053 | -1.33227e-15 | 21.2 | 2921.32 | 20.0053 | 0.5035
APTO10-PAREDE-013 | Terceiro Pavimento | yes | Parede -013 | 1051.67 (kgCO₂) | 13145.9 | 8000 | 2650 | 1.34 | 19.8973 | 3.04304 | 2650 | 5300 | 0 | 0 | 19.7893 | 8000 | 4.028 | 16380 | 7950 | 2650 | 2.29665 | 2 | 0 | 0 | 0 | 20.0053 | 4.44089e-16 | 21.2 | 2921.32 | 20.0053 | 0.5035
CIRC3-PAREDE-031 | Terceiro Pavimento | yes | Parede -031 | 375.516 (kgCO₂) | 4693.95 | 2400 | 2350 | 0.47025 | 5.71875 | 1.08656 | 2350 | 5150 | -150 | -450 | 5.71875 | 2475 | 1.08656 | 5180 | 7500 | 2200 | 1.3585 | 0 | 0 | 0 | 0 | 5.71875 | 0 | 5.71875 | 1043.1 | 5.71875 | 0.4465
APTO11-PAREDE-013 | Terceiro Pavimento | yes | Parede -013 | 1051.33 (kgCO₂) | 13141.6 | 8000 | 2500 | 1.34 | 19.892 | 3.04204 | 2650 | 5300 | 0 | 0 | 19.784 | 8000 | 4.028 | 16380 | 7800 | 2500 | 2.2615 | 2 | 0 | 0 | 0 | 20 | 0 | 21.2 | 2920.36 | 20 | 0.5035
APTO12-PAREDE-013 | Terceiro Pavimento | yes | Parede -013 | 1051.33 (kgCO₂) | 13141.6 | 8000 | 2500 | 1.34 | 19.892 | 3.04204 | 2650 | 5300 | 0 | 0 | 19.784 | 8000 | 4.028 | 16380 | 7800 | 2500 | 2.2615 | 2 | 0 | 0 | 0 | 20 | 0 | 21.2 | 2920.36 | 20 | 0.5035

# IfcWall: GENÉRICO - VEDAÇÃO EXTERNA 20 (24)
Classification: Parede (Classificação ARCHICAD); 3E 14 02 00 Parede (NBR 15965-5 3E); Material: GENÉRICO - VEDAÇÃO EXTERNA 20 mm
Pset_WallCommon - AcousticRating: 0,00; IsExternal: no; Status: EXISTING
CLASSIFICAÇÕES GERAIS - Transmissão Sonora: 0
SUPERFÍCIES (Mapas) - Superfície da Face (Geral): Pintura - Sienna Areia; Área da Superfície da Face (Geral): 0.0044 m2
Component Properties - GENÉRICO - VEDAÇÃO EXTERNA, Carbono Incorporado: 3.8016 (kgCO₂); GENÉRICO - VEDAÇÃO EXTERNA, Energia Incorporada: 47.52 MJ; GENÉRICO - VEDAÇÃO EXTERNA, Tipo de Componente: Nenhum
Qto_WallBaseQuantities - Length: 220 mm; Height: 2500 mm; Width: 20 mm; GrossFootprintArea: 0.0044 m2; NetFootprintArea: 0.0044 m2; GrossSideArea: 0.55 m2; NetSideArea: 0.55 m2; GrossVolume: 0.011 m3; NetVolume: 0.011 m3; GENÉRICO - VEDAÇÃO EXTERNA, Width: 20 mm
ArchiCADQuantities - Área: 0.0044 m2; Altura: 2650 mm; Volume (Líquido): 0.011 m3; Largura: 20 mm; Elevação ao Piso: 0 mm; Afastamento da Origem: 0 mm; Afastamento do Topo: 0 mm; Área da Superfície: 0.55 m2; Comprimento 3D: 220 mm; Espessura: 20 mm; Volume (Condicional): 0.011 m3; Volume (Bruto): 0.0159 m3; Espessura da Camada de Isolamento: 0 mm; Perímetro na Planta: 480 mm; Elevação do Topo Ao Piso de Origem: 2500 mm; Elevação da Base Ao Piso de Origem: 0 mm; Área da Superfície do Topo (Líquida): 0.0044 m2; Área da Superfície da Borda (Líquida): 0.0044 m2; Área da Superfície da Base (Líquida): 0.55 m2; Número de Portas: 0; Número de Furos (Número de Aberturas Vazias): 0; Número de Janelas: 0; Número de Pilares: 0; Volume dos Pilares: 0 m3; Altura Máxima da Camada da Parede na Face Interna: 0 mm; Altura Mínima da Camada da Parede na Face Interna: 0 mm; Altura máxima da parede: 2500 mm; Altura mínima da parede: 0 mm; Altura Máxima da Camada da Parede na Face Externa: 0 mm; Altura Mínima da Camada da Parede na Face Externa: 0 mm; Espessura da Camada de Ar: 0 mm; Área das Portas: 0 m2; Soma das Larguras das Portas: 0 mm; Espessura do Componente na Face Interna da Parede: 0 mm; Espessura do Componentena na Face Externa da Parede: 0 mm; Área das Janelas: 0 m2; Soma das Larguras das Janelas: 0 mm; Área Analítica da Superfície das Aberturas da Face Interna: 0 m2; Área Analítica da Superfície das Aberturas da Face Externa: 0 m2; Comprimento Médio da Parede: 220 mm; Área da Superfície da Face Interna da Parede (Líquida): 0.55 m2; Área da Superfície da Face Externa da Parede (Líquida): 0.55 m2; Volume Analítico das Aberturas: 0 m3; Comprimento da Linha de Referência: 300 mm; Comprimento da Face Interna da Parede (Condicional): 220 mm; Área da Superfície da Face Interna da Parede (Condicional): 0.55 m2; Comprimento da Face Externa da Parede (Condicional): 220 mm; Área da Superfície da Face Externa da Parede (Condicional): 0.55 m2; Área da Superfície da Face Interna da Parede (Bruta): 0.795 m2; Área da Superfície da Face Externa da Parede (Bruta): 0.795 m2; Espessura da Parede na Terminação: 20 mm; Comprimento da parede no centro: 220 mm; Comprimento da Parede na Face Interna: 220 mm; Comprimento da Parede na Face Externa: 220 mm; Área de Superfície do Vão na Parede: 0 m2
ALVENARIAS (Expressão) - Espessura da Argamassa: 10 mm
Component Quantities - GENÉRICO - VEDAÇÃO EXTERNA, Massa: 10.56 kg; GENÉRICO - VEDAÇÃO EXTERNA, Área de Componente Projetada (Líquida): 0.55 m2; GENÉRICO - VEDAÇÃO EXTERNA, Área de Componente Projetada (Bruta): 0.55 m2; GENÉRICO - VEDAÇÃO EXTERNA, Área de Componente Projetada (Condicional): 0.55 m2; GENÉRICO - VEDAÇÃO EXTERNA, Espessura do Componente: 20 mm; GENÉRICO - VEDAÇÃO EXTERNA, Altura do Componente Retangular: 2650 mm; GENÉRICO - VEDAÇÃO EXTERNA, Largura do Componente Retangular: 20 mm; GENÉRICO - VEDAÇÃO EXTERNA, Área de Seção Transversal do Componente: 0.053 m2; GENÉRICO - VEDAÇÃO EXTERNA, Volume Componente (Líquido): 0.011 m3; GENÉRICO - VEDAÇÃO EXTERNA, Volume do componente (Bruto): 0.011 m3; GENÉRICO - VEDAÇÃO EXTERNA, Volume Componente (Condicional): 0.011 m3
Name | In | ID Dinâmico por Classificação | Elevação à Origem do Projeto (mm) = Elevação ao 1º Nível de Referência (mm) = Elevação ao 2º Nível de Referência (mm) = Elevação ao Nível do Mar (mm) = Elevação da Base Ao Primeiro Nível de Referência (mm) = Elevação da Base À Cota Zero (mm) = Elevação da Base Ao Nível do Mar (mm) = Elevação da Base Ao Segundo Nível de Referência (mm) | Elevação do Topo ao Primeiro Nível de Referência (mm) = Elevação do Topo À Cota Zero (mm) = Elevação do Topo Ao Nível do Mar (mm) = Elevação do Topo Ao Segundo Nível de Referência (mm)
APTO4-PAREDE-009 | Primeiro Pavimento | Parede -009 | 0 | 2500
APTO4-PAREDE-008 | Primeiro Pavimento | Parede -008 | 0 | 2500
APTO2-PAREDE-009 | Primeiro Pavimento | Parede -009 | 0 | 2500
APTO2-PAREDE-008 | Primeiro Pavimento | Parede -008 | 0 | 2500
APTO3-PAREDE-009 | Primeiro Pavimento | Parede -009 | 0 | 2500
APTO3-PAREDE-008 | Primeiro Pavimento | Parede -008 | 0 | 2500
APTO1-PAREDE-008 | Primeiro Pavimento | Parede -008 | 0 | 2500
APTO1-PAREDE-009 | Primeiro Pavimento | Parede -009 | 0 | 2500
APTO5-PAREDE-009 | Segundo Pavimento | Parede -009 | 2650 | 5150
APTO5-PAREDE-008 | Segundo Pavimento | Parede -008 | 2650 | 5150
APTO6-PAREDE-009 | Segundo Pavimento | Parede -009 | 2650 | 5150
APTO6-PAREDE-008 | Segundo Pavimento | Parede -008 | 2650 | 5150
APTO7-PAREDE-009 | Segundo Pavimento | Parede -009 | 2650 | 5150
APTO7-PAREDE-008 | Segundo Pavimento | Parede -008 | 2650 | 5150
APTO8-PAREDE-009 | Segundo Pavimento | Parede -009 | 2650 | 5150
APTO8-PAREDE-008 | Segundo Pavimento | Parede -008 | 2650 | 5150
APTO9-PAREDE-009 | Terceiro Pavimento | Parede -009 | 5300 | 7800
APTO9-PAREDE-008 | Terceiro Pavimento | Parede -008 | 5300 | 7800
APTO10-PAREDE-009 | Terceiro Pavimento | Parede -009 | 5300 | 7800
APTO10-PAREDE-008 | Terceiro Pavimento | Parede -008 | 5300 | 7800
APTO11-PAREDE-009 | Terceiro Pavimento | Parede -009 | 5300 | 7800
APTO11-PAREDE-008 | Terceiro Pavimento | Parede -008 | 5300 | 7800
APTO12-PAREDE-009 | Terceiro Pavimento | Parede -009 | 5300 | 7800
APTO12-PAREDE-008 | Terceiro Pavimento | Parede -008 | 5300 | 7800

# IfcWall: GENÉRICO - VEDAÇÃO EXTERNA 40 (72)
Classification: Parede (Classificação ARCHICAD); 3E 14 02 00 Parede (NBR 15965-5 3E); Material: GENÉRICO - VEDAÇÃO EXTERNA 40 mm
Pset_WallCommon - AcousticRating: 0,00; IsExternal: no; Status: EXISTING
CLASSIFICAÇÕES GERAIS - Transmissão Sonora: 0
SUPERFÍCIES (Mapas) - Superfície da Face (Geral): Pintura - Sienna Areia
Component Properties - GENÉRICO - VEDAÇÃO EXTERNA, Tipo de Componente: Nenhum
Qto_WallBaseQuantities - Width: 40 mm; GENÉRICO - VEDAÇÃO EXTERNA, Width: 40 mm
ArchiCADQuantities - Largura: 40 mm; Elevação ao Piso: 0 mm; Afastamento da Origem: 0 mm; Espessura: 40 mm; Espessura da Camada de Isolamento: 0 mm; Elevação da Base Ao Piso de Origem: 0 mm; Número de Furos (Número de Aberturas Vazias): 0; Número de Janelas: 0; Número de Pilares: 0; Volume dos Pilares: 0 m3; Altura Máxima da Camada da Parede na Face Interna: 0 mm; Altura Mínima da Camada da Parede na Face Interna: 0 mm; Altura Máxima da Camada da Parede na Face Externa: 0 mm; Altura Mínima da Camada da Parede na Face Externa: 0 mm; Espessura da Camada de Ar: 0 mm; Espessura do Componente na Face Interna da Parede: 0 mm; Espessura do Componentena na Face Externa da Parede: 0 mm; Área das Janelas: 0 m2; Soma das Larguras das Janelas: 0 mm; Espessura da Parede na Terminação: 40 mm; Área de Superfície do Vão na Parede: 0 m2
ALVENARIAS (Expressão) - Espessura da Argamassa: 10 mm
Component Quantities - GENÉRICO - VEDAÇÃO EXTERNA, Espessura do Componente: 40 mm; GENÉRICO - VEDAÇÃO EXTERNA, Largura do Componente Retangular: 40 mm
Name | In | ID Dinâmico por Classificação | GENÉRICO - VEDAÇÃO EXTERNA, Carbono Incorporado | GENÉRICO - VEDAÇÃO EXTERNA, Energia Incorporada (MJ) | Length (mm) = Comprimento 3D (mm) = Comprimento Médio da Parede (mm) = Comprimento da parede no centro (mm) = Comprimento da Parede na Face Interna (mm) = Comprimento da Parede na Face Externa (mm) | Height (mm) = Elevação do Topo Ao Piso de Origem (mm) = Altura máxima da parede (mm) | GrossFootprintArea (m2) = NetFootprintArea (m2) = Área (m2) = Área da Superfície do Topo (Líquida) (m2) | GrossSideArea (m2) = Área da Superfície da Face Interna da Parede (Condicional) (m2) = Área da Superfície da Face Externa da Parede (Condicional) (m2) = GENÉRICO - VEDAÇÃO EXTERNA, Área de Componente Projetada (Bruta) (m2) = GENÉRICO - VEDAÇÃO EXTERNA, Área de Componente Projetada (Condicional) (m2) | NetSideArea (m2) = Área da Superfície (m2) = Área da Superfície da Base (Líquida) (m2) = Área da Superfície da Face Interna da Parede (Líquida) (m2) = Área da Superfície da Face Externa da Parede (Líquida) (m2) = GENÉRICO - VEDAÇÃO EXTERNA, Área de Componente Projetada (Líquida) (m2) | GrossVolume (m3) = Volume (Condicional) (m3) = GENÉRICO - VEDAÇÃO EXTERNA, Volume do componente (Bruto) (m3) = GENÉRICO - VEDAÇÃO EXTERNA, Volume Componente (Condicional) (m3) | NetVolume (m3) = Volume (Líquido) (m3) = GENÉRICO - VEDAÇÃO EXTERNA, Volume Componente (Líquido) (m3) | Altura (mm) = GENÉRICO - VEDAÇÃO EXTERNA, Altura do Componente Retangular (mm) | Elevação à Origem do Projeto (mm) = Elevação ao 1º Nível de Referência (mm) = Elevação ao 2º Nível de Referência (mm) = Elevação ao Nível do Mar (mm) = Elevação da Base Ao Primeiro Nível de Referência (mm) = Elevação da Base À Cota Zero (mm) = Elevação da Base Ao Nível do Mar (mm) = Elevação da Base Ao Segundo Nível de Referência (mm) | Afastamento do Topo (mm) | Volume (Bruto) (m3) | Perímetro na Planta (mm) | Elevação do Topo ao Primeiro Nível de Referência (mm) = Elevação do Topo À Cota Zero (mm) = Elevação do Topo Ao Nível do Mar (mm) = Elevação do Topo Ao Segundo Nível de Referência (mm) | Área da Superfície da Borda (Líquida) (m2) = Área da Superfície da Face (Geral) (m2) | Número de Portas | Altura mínima da parede (mm) | Área das Portas (m2) | Soma das Larguras das Portas (mm) | Área Analítica da Superfície das Aberturas da Face Interna (m2) | Área Analítica da Superfície das Aberturas da Face Externa (m2) | Volume Analítico das Aberturas (m3) | Comprimento da Linha de Referência (mm) | Comprimento da Face Interna da Parede (Condicional) (mm) = Comprimento da Face Externa da Parede (Condicional) (mm) | Área da Superfície da Face Interna da Parede (Bruta) (m2) = Área da Superfície da Face Externa da Parede (Bruta) (m2) | GENÉRICO - VEDAÇÃO EXTERNA, Massa (kg) | GENÉRICO - VEDAÇÃO EXTERNA, Área de Seção Transversal do Componente (m2)
APTO4-PAREDE-003 | Primeiro Pavimento | Parede -003 | 127.54 (kgCO₂) | 1594.25 | 3750 | 2500 | 0.15 | 9.226 | 9.226 | 0.36904 | 0.36904 | 2620 | 0 | -30 | 0.393 | 7580 | 2500 | 0.3212 | 0 | 0 | 0 | 0 | 3.55271e-15 | 5.32907e-15 | -5.55112e-17 | 3750 | 3750 | 9.825 | 354.278 | 0.1048
APTO4-PAREDE-011 | Primeiro Pavimento | Parede -011 | 46.656 (kgCO₂) | 583.2 | 1350 | 2500 | 0.054 | 3.375 | 3.375 | 0.135 | 0.135 | 2650 | 0 | 0 | 0.17278 | 2780 | 2500 | 0.054 | 0 | 0 | 0 | 0 | 0 | 0 | 0 | 1440 | 1350 | 4.3195 | 129.6 | 0.106
APTO4-PAREDE-005 | Primeiro Pavimento | Parede -005 | 117.62 (kgCO₂) | 1470.25 | 3465 | 2500 | 0.1386 | 8.50837 | 8.50837 | 0.340335 | 0.340335 | 2620 | 0 | -30 | 0.363132 | 7010 | 2500 | 0.2974 | 0 | 0 | 0 | 0 | 5.32907e-15 | 5.32907e-15 | -1.66533e-16 | 3465 | 3465 | 9.0783 | 326.721 | 0.1048
APTO4-PAREDE-006 | Primeiro Pavimento | Parede -006 | 77.3315 (kgCO₂) | 966.644 | 5120 | 2200 | 0.0968001 | 11.264 | 5.594 | 0.45056 | 0.22376 | 2650 | 0 | 0 | 0.56172 | 10320 | 2200 | 0.1008 | 3 | 0 | 5.67 | 2700 | 5.67 | 5.67 | 0.2268 | 5120 | 2420 | 14.043 | 214.81 | 0.106
APTO4-PAREDE-007 | Primeiro Pavimento | Parede -007 | 117.62 (kgCO₂) | 1470.25 | 3465 | 2500 | 0.1386 | 8.50837 | 8.50837 | 0.340335 | 0.340335 | 2650 | 0 | 0 | 0.36729 | 7010 | 2500 | 0.2974 | 0 | 0 | 0 | 0 | 7.10543e-15 | 7.10543e-15 | -2.22045e-16 | 3465 | 3465 | 9.18225 | 326.721 | 0.106
APTO4-PAREDE-010 | Primeiro Pavimento | Parede -010 | 46.656 (kgCO₂) | 583.2 | 1350 | 2500 | 0.054 | 3.375 | 3.375 | 0.135 | 0.135 | 2650 | 0 | 0 | 0.17278 | 2780 | 2500 | 0.054 | 0 | 0 | 0 | 0 | 0 | 0 | 0 | 1440 | 1350 | 4.3195 | 129.6 | 0.106
APTO3-PAREDE-006 | Primeiro Pavimento | Parede -006 | 77.3315 (kgCO₂) | 966.643 | 5120 | 2200 | 0.0968 | 11.264 | 5.594 | 0.45056 | 0.22376 | 2650 | 0 | 0 | 0.54272 | 10320 | 2200 | 0.1888 | 3 | 2200 | 5.67 | 2700 | 5.67 | 5.67 | 0.2268 | 5120 | 2420 | 13.568 | 214.81 | 0.106
APTO2-PAREDE-003 | Primeiro Pavimento | Parede -003 | 127.54 (kgCO₂) | 1594.25 | 3750 | 2500 | 0.15 | 9.226 | 9.226 | 0.36904 | 0.36904 | 2620 | 0 | -30 | 0.393 | 7580 | 2500 | 0.3212 | 0 | 0 | 0 | 0 | 1.06581e-14 | 8.88178e-15 | 4.996e-16 | 3750 | 3750 | 9.825 | 354.278 | 0.1048
APTO2-PAREDE-011 | Primeiro Pavimento | Parede -011 | 46.656 (kgCO₂) | 583.2 | 1350 | 2500 | 0.054 | 3.375 | 3.375 | 0.135 | 0.135 | 2650 | 0 | 0 | 0.17278 | 2780 | 2500 | 0.054 | 0 | 0 | 0 | 0 | 0 | 0 | 0 | 1440 | 1350 | 4.3195 | 129.6 | 0.106
APTO2-PAREDE-005 | Primeiro Pavimento | Parede -005 | 117.62 (kgCO₂) | 1470.25 | 3465 | 2500 | 0.1386 | 8.50837 | 8.50837 | 0.340335 | 0.340335 | 2620 | 0 | -30 | 0.363132 | 7010 | 2500 | 0.2974 | 0 | 0 | 0 | 0 | 1.24345e-14 | 1.42109e-14 | 6.10623e-16 | 3465 | 3465 | 9.0783 | 326.721 | 0.1048
APTO2-PAREDE-010 | Primeiro Pavimento | Parede -010 | 46.656 (kgCO₂) | 583.2 | 1350 | 2500 | 0.054 | 3.375 | 3.375 | 0.135 | 0.135 | 2650 | 0 | 0 | 0.17278 | 2780 | 2500 | 0.054 | 0 | 0 | 0 | 0 | 0 | 0 | 0 | 1440 | 1350 | 4.3195 | 129.6 | 0.106
APTO2-PAREDE-007 | Primeiro Pavimento | Parede -007 | 117.62 (kgCO₂) | 1470.25 | 3465 | 2500 | 0.1386 | 8.50837 | 8.50837 | 0.340335 | 0.340335 | 2650 | 0 | 0 | 0.36729 | 7010 | 2500 | 0.2974 | 0 | 0 | 0 | 0 | 1.06581e-14 | 1.06581e-14 | 9.9365e-15 | 3465 | 3465 | 9.18225 | 326.721 | 0.106
APTO2-PAREDE-006 | Primeiro Pavimento | Parede -006 | 77.3315 (kgCO₂) | 966.644 | 5120 | 2200 | 0.0968001 | 11.264 | 5.594 | 0.45056 | 0.22376 | 2650 | 0 | 0 | 0.561492 | 10320 | 2200 | 0.1008 | 3 | 0 | 5.67 | 2700 | 5.67 | 5.67 | 0.2268 | 5120 | 2420 | 14.0373 | 214.81 | 0.106
APTO3-PAREDE-003 | Primeiro Pavimento | Parede -003 | 127.54 (kgCO₂) | 1594.25 | 3750 | 2500 | 0.15 | 9.226 | 9.226 | 0.36904 | 0.36904 | 2620 | 0 | -30 | 0.393 | 7580 | 2500 | 0.3212 | 0 | 0 | 0 | 0 | 5.32907e-15 | 5.32907e-15 | 1.11022e-16 | 3750 | 3750 | 9.825 | 354.278 | 0.1048
APTO3-PAREDE-011 | Primeiro Pavimento | Parede -011 | 46.656 (kgCO₂) | 583.2 | 1350 | 2500 | 0.054 | 3.375 | 3.375 | 0.135 | 0.135 | 2650 | 0 | 0 | 0.17278 | 2780 | 2500 | 0.054 | 0 | 0 | 0 | 0 | 0 | 0 | 0 | 1440 | 1350 | 4.3195 | 129.6 | 0.106
APTO3-PAREDE-005 | Primeiro Pavimento | Parede -005 | 117.62 (kgCO₂) | 1470.25 | 3465 | 2500 | 0.1386 | 8.50837 | 8.50837 | 0.340335 | 0.340335 | 2620 | 0 | -30 | 0.363132 | 7010 | 2500 | 0.2974 | 0 | 0 | 0 | 0 | 3.55271e-15 | 3.55271e-15 | -4.44089e-16 | 3465 | 3465 | 9.0783 | 326.721 | 0.1048
APTO3-PAREDE-010 | Primeiro Pavimento | Parede -010 | 46.656 (kgCO₂) | 583.2 | 1350 | 2500 | 0.054 | 3.375 | 3.375 | 0.135 | 0.135 | 2650 | 0 | 0 | 0.17278 | 2780 | 2500 | 0.054 | 0 | 0 | 0 | 0 | 0 | 0 | 0 | 1440 | 1350 | 4.3195 | 129.6 | 0.106
APTO3-PAREDE-007 | Primeiro Pavimento | Parede -007 | 117.62 (kgCO₂) | 1470.25 | 3465 | 2500 | 0.1386 | 8.50837 | 8.50837 | 0.340335 | 0.340335 | 2650 | 0 | 0 | 0.36729 | 7010 | 2500 | 0.2974 | 0 | 0 | 0 | 0 | 8.88178e-15 | 7.10543e-15 | -1.88738e-15 | 3465 | 3465 | 9.18225 | 326.721 | 0.106
APTO1-PAREDE-006 | Primeiro Pavimento | Parede -006 | 77.3315 (kgCO₂) | 966.643 | 5120 | 2200 | 0.0968 | 11.264 | 5.594 | 0.45056 | 0.22376 | 2650 | 0 | 0 | 0.54272 | 10320 | 2200 | 0.1888 | 3 | 2200 | 5.67 | 2700 | 5.67 | 5.67 | 0.2268 | 5120 | 2420 | 13.568 | 214.81 | 0.106
APTO1-PAREDE-007 | Primeiro Pavimento | Parede -007 | 117.62 (kgCO₂) | 1470.25 | 3465 | 2500 | 0.1386 | 8.50837 | 8.50837 | 0.340335 | 0.340335 | 2650 | 0 | 0 | 0.36729 | 7010 | 2500 | 0.2974 | 0 | 0 | 0 | 0 | 1.06581e-14 | 1.24345e-14 | 4.44089e-16 | 3465 | 3465 | 9.18225 | 326.721 | 0.106
APTO1-PAREDE-010 | Primeiro Pavimento | Parede -010 | 46.656 (kgCO₂) | 583.2 | 1350 | 2500 | 0.054 | 3.375 | 3.375 | 0.135 | 0.135 | 2650 | 0 | 0 | 0.17278 | 2780 | 2500 | 0.054 | 0 | 0 | 0 | 0 | 0 | 0 | 0 | 1440 | 1350 | 4.3195 | 129.6 | 0.106
APTO1-PAREDE-005 | Primeiro Pavimento | Parede -005 | 117.62 (kgCO₂) | 1470.25 | 3465 | 2500 | 0.1386 | 8.50837 | 8.50837 | 0.340335 | 0.340335 | 2620 | 0 | -30 | 0.363132 | 7010 | 2500 | 0.2974 | 0 | 0 | 0 | 0 | 1.24345e-14 | 1.24345e-14 | -5.55112e-17 | 3465 | 3465 | 9.0783 | 326.721 | 0.1048
APTO1-PAREDE-011 | Primeiro Pavimento | Parede -011 | 46.656 (kgCO₂) | 583.2 | 1350 | 2500 | 0.054 | 3.375 | 3.375 | 0.135 | 0.135 | 2650 | 0 | 0 | 0.17278 | 2780 | 2500 | 0.054 | 0 | 0 | 0 | 0 | 0 | 0 | 0 | 1440 | 1350 | 4.3195 | 129.6 | 0.106
APTO1-PAREDE-003 | Primeiro Pavimento | Parede -003 | 127.54 (kgCO₂) | 1594.25 | 3750 | 2500 | 0.15 | 9.226 | 9.226 | 0.36904 | 0.36904 | 2620 | 0 | -30 | 0.393 | 7580 | 2500 | 0.3212 | 0 | 0 | 0 | 0 | 1.06581e-14 | 1.06581e-14 | 4.44089e-16 | 3750 | 3750 | 9.825 | 354.278 | 0.1048
APTO5-PAREDE-006 | Segundo Pavimento | Parede -006 | 77.3315 (kgCO₂) | 966.643 | 5120 | 2200 | 0.0968 | 11.264 | 5.594 | 0.45056 | 0.22376 | 2650 | 2650 | 0 | 0.54272 | 10320 | 4850 | 0.1888 | 3 | 2200 | 5.67 | 2700 | 5.67 | 5.67 | 0.2268 | 5120 | 2420 | 13.568 | 214.81 | 0.106
APTO5-PAREDE-007 | Segundo Pavimento | Parede -007 | 117.62 (kgCO₂) | 1470.25 | 3465 | 2500 | 0.1386 | 8.50837 | 8.50837 | 0.340335 | 0.340335 | 2650 | 2650 | 0 | 0.36729 | 7010 | 5150 | 0.2974 | 0 | 3.55271e-12 | 0 | 0 | 1.24345e-14 | 1.24345e-14 | 3.88578e-16 | 3465 | 3465 | 9.18225 | 326.721 | 0.106
APTO5-PAREDE-003 | Segundo Pavimento | Parede -003 | 127.54 (kgCO₂) | 1594.25 | 3750 | 2500 | 0.15 | 9.226 | 9.226 | 0.36904 | 0.36904 | 2620 | 2650 | -30 | 0.393 | 7580 | 5150 | 0.3212 | 0 | 3.55271e-12 | 0 | 0 | 8.88178e-15 | 1.24345e-14 | 4.44089e-16 | 3750 | 3750 | 9.825 | 354.278 | 0.1048
APTO5-PAREDE-011 | Segundo Pavimento | Parede -011 | 46.656 (kgCO₂) | 583.2 | 1350 | 2500 | 0.054 | 3.375 | 3.375 | 0.135 | 0.135 | 2650 | 2650 | 0 | 0.17278 | 2780 | 5150 | 0.054 | 0 | 0 | 0 | 0 | 0 | 0 | 0 | 1440 | 1350 | 4.3195 | 129.6 | 0.106
APTO5-PAREDE-005 | Segundo Pavimento | Parede -005 | 117.62 (kgCO₂) | 1470.25 | 3465 | 2500 | 0.1386 | 8.50837 | 8.50837 | 0.340335 | 0.340335 | 2620 | 2650 | -30 | 0.363132 | 7010 | 5150 | 0.2974 | 0 | 3.55271e-12 | 0 | 0 | 1.42109e-14 | 1.24345e-14 | 2.77556e-16 | 3465 | 3465 | 9.0783 | 326.721 | 0.1048
APTO5-PAREDE-010 | Segundo Pavimento | Parede -010 | 46.656 (kgCO₂) | 583.2 | 1350 | 2500 | 0.054 | 3.375 | 3.375 | 0.135 | 0.135 | 2650 | 2650 | 0 | 0.17278 | 2780 | 5150 | 0.054 | 0 | 0 | 0 | 0 | 0 | 0 | 0 | 1440 | 1350 | 4.3195 | 129.6 | 0.106
APTO6-PAREDE-003 | Segundo Pavimento | Parede -003 | 127.54 (kgCO₂) | 1594.25 | 3750 | 2500 | 0.15 | 9.226 | 9.226 | 0.36904 | 0.36904 | 2620 | 2650 | -30 | 0.393 | 7580 | 5150 | 0.3212 | 0 | 3.55271e-12 | 0 | 0 | 1.24345e-14 | 7.10543e-15 | 6.66134e-16 | 3750 | 3750 | 9.825 | 354.278 | 0.1048
APTO6-PAREDE-011 | Segundo Pavimento | Parede -011 | 46.656 (kgCO₂) | 583.2 | 1350 | 2500 | 0.054 | 3.375 | 3.375 | 0.135 | 0.135 | 2650 | 2650 | 0 | 0.17278 | 2780 | 5150 | 0.054 | 0 | 0 | 0 | 0 | 0 | 0 | 0 | 1440 | 1350 | 4.3195 | 129.6 | 0.106
APTO6-PAREDE-005 | Segundo Pavimento | Parede -005 | 117.62 (kgCO₂) | 1470.25 | 3465 | 2500 | 0.1386 | 8.50837 | 8.50837 | 0.340335 | 0.340335 | 2620 | 2650 | -30 | 0.363132 | 7010 | 5150 | 0.2974 | 0 | 3.55271e-12 | 0 | 0 | 1.24345e-14 | 1.42109e-14 | 4.996e-16 | 3465 | 3465 | 9.0783 | 326.721 | 0.1048
APTO6-PAREDE-010 | Segundo Pavimento | Parede -010 | 46.656 (kgCO₂) | 583.2 | 1350 | 2500 | 0.054 | 3.375 | 3.375 | 0.135 | 0.135 | 2650 | 2650 | 0 | 0.17278 | 2780 | 5150 | 0.054 | 0 | 0 | 0 | 0 | 0 | 0 | 0 | 1440 | 1350 | 4.3195 | 129.6 | 0.106
APTO6-PAREDE-007 | Segundo Pavimento | Parede -007 | 117.62 (kgCO₂) | 1470.25 | 3465 | 2500 | 0.1386 | 8.50837 | 8.50837 | 0.340335 | 0.340335 | 2650 | 2650 | 0 | 0.36729 | 7010 | 5150 | 0.2974 | 0 | 3.55271e-12 | 0 | 0 | 1.24345e-14 | 1.59872e-14 | -2.22045e-16 | 3465 | 3465 | 9.18225 | 326.721 | 0.106
APTO6-PAREDE-006 | Segundo Pavimento | Parede -006 | 77.3315 (kgCO₂) | 966.644 | 5120 | 2200 | 0.0968001 | 11.264 | 5.594 | 0.45056 | 0.22376 | 2650 | 2650 | 0 | 0.561492 | 10320 | 4850 | 0.1008 | 3 | 0 | 5.67 | 2700 | 5.67 | 5.67 | 0.2268 | 5120 | 2420 | 14.0373 | 214.81 | 0.106
APTO7-PAREDE-003 | Segundo Pavimento | Parede -003 | 127.54 (kgCO₂) | 1594.25 | 3750 | 2500 | 0.15 | 9.226 | 9.226 | 0.36904 | 0.36904 | 2620 | 2650 | -30 | 0.393 | 7580 | 5150 | 0.3212 | 0 | 3.55271e-12 | 0 | 0 | 7.10543e-15 | 5.32907e-15 | 5.55112e-17 | 3750 | 3750 | 9.825 | 354.278 | 0.1048
APTO7-PAREDE-011 | Segundo Pavimento | Parede -011 | 46.656 (kgCO₂) | 583.2 | 1350 | 2500 | 0.054 | 3.375 | 3.375 | 0.135 | 0.135 | 2650 | 2650 | 0 | 0.17278 | 2780 | 5150 | 0.054 | 0 | 0 | 0 | 0 | 0 | 0 | 0 | 1440 | 1350 | 4.3195 | 129.6 | 0.106
APTO7-PAREDE-005 | Segundo Pavimento | Parede -005 | 117.62 (kgCO₂) | 1470.25 | 3465 | 2500 | 0.1386 | 8.50837 | 8.50837 | 0.340335 | 0.340335 | 2620 | 2650 | -30 | 0.363132 | 7010 | 5150 | 0.2974 | 0 | 3.55271e-12 | 0 | 0 | 3.55271e-15 | 5.32907e-15 | -3.88578e-16 | 3465 | 3465 | 9.0783 | 326.721 | 0.1048
APTO7-PAREDE-010 | Segundo Pavimento | Parede -010 | 46.656 (kgCO₂) | 583.2 | 1350 | 2500 | 0.054 | 3.375 | 3.375 | 0.135 | 0.135 | 2650 | 2650 | 0 | 0.17278 | 2780 | 5150 | 0.054 | 0 | 0 | 0 | 0 | 0 | 0 | 0 | 1440 | 1350 | 4.3195 | 129.6 | 0.106
APTO7-PAREDE-007 | Segundo Pavimento | Parede -007 | 117.62 (kgCO₂) | 1470.25 | 3465 | 2500 | 0.1386 | 8.50837 | 8.50837 | 0.340335 | 0.340335 | 2650 | 2650 | 0 | 0.36729 | 7010 | 5150 | 0.2974 | 0 | 3.55271e-12 | 0 | 0 | 7.10543e-15 | 7.10543e-15 | -1.27676e-15 | 3465 | 3465 | 9.18225 | 326.721 | 0.106
APTO7-PAREDE-006 | Segundo Pavimento | Parede -006 | 77.3315 (kgCO₂) | 966.643 | 5120 | 2200 | 0.0968 | 11.264 | 5.594 | 0.45056 | 0.22376 | 2650 | 2650 | 0 | 0.54272 | 10320 | 4850 | 0.1888 | 3 | 2200 | 5.67 | 2700 | 5.67 | 5.67 | 0.2268 | 5120 | 2420 | 13.568 | 214.81 | 0.106
APTO8-PAREDE-003 | Segundo Pavimento | Parede -003 | 127.54 (kgCO₂) | 1594.25 | 3750 | 2500 | 0.15 | 9.226 | 9.226 | 0.36904 | 0.36904 | 2620 | 2650 | -30 | 0.393 | 7580 | 5150 | 0.3212 | 0 | 3.55271e-12 | 0 | 0 | 7.10543e-15 | 8.88178e-15 | 1.11022e-16 | 3750 | 3750 | 9.825 | 354.278 | 0.1048
APTO8-PAREDE-011 | Segundo Pavimento | Parede -011 | 46.656 (kgCO₂) | 583.2 | 1350 | 2500 | 0.054 | 3.375 | 3.375 | 0.135 | 0.135 | 2650 | 2650 | 0 | 0.17278 | 2780 | 5150 | 0.054 | 0 | 0 | 0 | 0 | 0 | 0 | 0 | 1440 | 1350 | 4.3195 | 129.6 | 0.106
APTO8-PAREDE-005 | Segundo Pavimento | Parede -005 | 117.62 (kgCO₂) | 1470.25 | 3465 | 2500 | 0.1386 | 8.50837 | 8.50837 | 0.340335 | 0.340335 | 2620 | 2650 | -30 | 0.363132 | 7010 | 5150 | 0.2974 | 0 | 3.55271e-12 | 0 | 0 | 5.32907e-15 | 5.32907e-15 | -1.66533e-16 | 3465 | 3465 | 9.0783 | 326.721 | 0.1048
APTO8-PAREDE-010 | Segundo Pavimento | Parede -010 | 46.656 (kgCO₂) | 583.2 | 1350 | 2500 | 0.054 | 3.375 | 3.375 | 0.135 | 0.135 | 2650 | 2650 | 0 | 0.17278 | 2780 | 5150 | 0.054 | 0 | 0 | 0 | 0 | 0 | 0 | 0 | 1440 | 1350 | 4.3195 | 129.6 | 0.106
APTO8-PAREDE-007 | Segundo Pavimento | Parede -007 | 117.62 (kgCO₂) | 1470.25 | 3465 | 2500 | 0.1386 | 8.50837 | 8.50837 | 0.340335 | 0.340335 | 2650 | 2650 | 0 | 0.36729 | 7010 | 5150 | 0.2974 | 0 | 3.55271e-12 | 0 | 0 | 7.10543e-15 | 7.10543e-15 | -2.77556e-16 | 3465 | 3465 | 9.18225 | 326.721 | 0.106
APTO8-PAREDE-006 | Segundo Pavimento | Parede -006 | 77.3315 (kgCO₂) | 966.644 | 5120 | 2200 | 0.0968001 | 11.264 | 5.594 | 0.45056 | 0.22376 | 2650 | 2650 | 0 | 0.56172 | 10320 | 4850 | 0.1008 | 3 | 0 | 5.67 | 2700 | 5.67 | 5.67 | 0.2268 | 5120 | 2420 | 14.043 | 214.81 | 0.106
APTO9-PAREDE-003 | Terceiro Pavimento | Parede -003 | 127.54 (kgCO₂) | 1594.25 | 3750 | 2500 | 0.15 | 9.226 | 9.226 | 0.36904 | 0.36904 | 2620 | 5300 | -30 | 0.393 | 7580 | 7800 | 0.3212 | 0 | 4.44089e-12 | 0 | 0 | 1.24345e-14 | 1.24345e-14 | 4.996e-16 | 3750 | 3750 | 9.825 | 354.278 | 0.1048
APTO9-PAREDE-011 | Terceiro Pavimento | Parede -011 | 46.656 (kgCO₂) | 583.2 | 1350 | 2500 | 0.054 | 3.375 | 3.375 | 0.135 | 0.135 | 2650 | 5300 | 0 | 0.17278 | 2780 | 7800 | 0.054 | 0 | 0 | 0 | 0 | 0 | 0 | 0 | 1440 | 1350 | 4.3195 | 129.6 | 0.106
APTO9-PAREDE-005 | Terceiro Pavimento | Parede -005 | 117.62 (kgCO₂) | 1470.25 | 3465 | 2500 | 0.1386 | 8.50837 | 8.50837 | 0.340335 | 0.340335 | 2620 | 5300 | -30 | 0.363132 | 7010 | 7800 | 0.2974 | 0 | 4.44089e-12 | 0 | 0 | 1.06581e-14 | 1.06581e-14 | -5.60663e-15 | 3465 | 3465 | 9.0783 | 326.721 | 0.1048
APTO9-PAREDE-010 | Terceiro Pavimento | Parede -010 | 46.656 (kgCO₂) | 583.2 | 1350 | 2500 | 0.054 | 3.375 | 3.375 | 0.135 | 0.135 | 2650 | 5300 | 0 | 0.17278 | 2780 | 7800 | 0.054 | 0 | 0 | 0 | 0 | 0 | 0 | 0 | 1440 | 1350 | 4.3195 | 129.6 | 0.106
APTO9-PAREDE-007 | Terceiro Pavimento | Parede -007 | 117.62 (kgCO₂) | 1470.25 | 3465 | 2500 | 0.1386 | 8.50837 | 8.50837 | 0.340335 | 0.340335 | 2650 | 5300 | 0 | 0.36729 | 7010 | 7800 | 0.2974 | 0 | 4.44089e-12 | 0 | 0 | 7.10543e-15 | 1.06581e-14 | 3.33067e-16 | 3465 | 3465 | 9.18225 | 326.721 | 0.106
APTO9-PAREDE-006 | Terceiro Pavimento | Parede -006 | 77.3315 (kgCO₂) | 966.643 | 5120 | 2200 | 0.0968 | 11.264 | 5.594 | 0.45056 | 0.22376 | 2650 | 5300 | 0 | 0.54272 | 10320 | 7500 | 0.1888 | 3 | 2200 | 5.67 | 2700 | 5.67 | 5.67 | 0.2268 | 5120 | 2420 | 13.568 | 214.81 | 0.106
